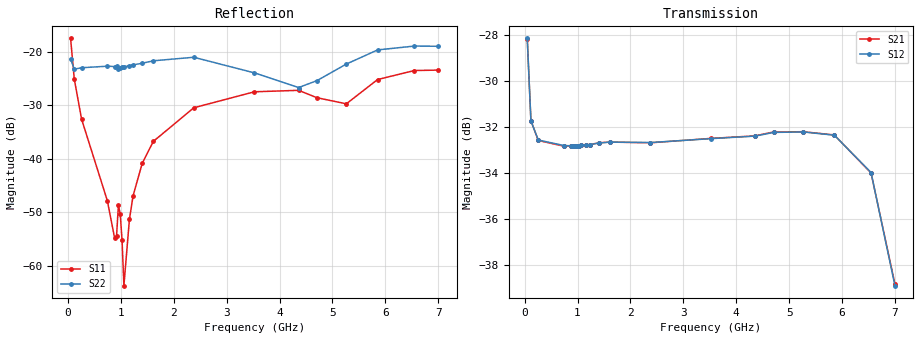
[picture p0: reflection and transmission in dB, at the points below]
! Integrated Device Technology
! Corporate Headquarters
! 6024 Silver Creek Valley Road
! San Jose, CA 95138  USA
! Phone:  1-408-284-8200
! Toll Free:  1-800-223-1366
! Webpage:  http://www.idt.com/
! Timing and RF Division
! 515 Groton Road, Suite 102
! Westford, MA 01886-6024
! Device:  F2258
! Description: Voltage Variable RF Attenuator
! Frequency:  50.0 -  6000.00 MHz
! Package:  3x3 mm Thin QFN Plastic Package: 16 pin
! Ports:  2 RF, 2 DC
!  Pin  1  = NC
!  Pin  2  = NC
!  Pin  3  = RF2  = Port 2
!  Pin  4  = GND
!  Pin  5  = Vdd
!  Pin  6  = NC
!  Pin  7  = VCTRL
!  Pin  8  = NC
!  Pin  9  = GND
!  Pin 10  = RF1  = Port 1
!  Pin 11  = NC
!  Pin 12  = NC
!  Pin 13  = NC
!  Pin 14  = NC
!  Pin 15  = NC
!  Pin 16  = NC
! Vcntrl:  1.770 Volts
! Vdd:  +3.300 Volts
! Current:  1.158 mA
! Data:  The device was measured on a the F2258 evaluation board which has
!  individual transmission lines to the RF pins.  Data was collected
!  using a calibrated network analyzer.  The evaluation board was
!  de-embedded using a TRL calibration technique.
!  The reference plane is the edge of the package pin.
! Misc:  SN 10
!  Action Tracker AT0285
! Date Measured:  2014-12-10
! Date:  2016-01-13  MJV
! Note:
!  Integrated Device Technology supplies this data as a sample of measured
!  data at the package pin for this product.  Your particular data for this
!  product may vary.
!  Data was taken at 25 degrees C.
!  Integrated Device Technology reserves the right to change this data at anytime.
!Freq_(GHz)  S11M_(dB)  S11P_(deg)  S21M_(dB)  S21P_(deg)  S12M_(dB)  S12P_(deg)  S22M_(dB)  S22P_(deg)
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# GHz S dB R 50
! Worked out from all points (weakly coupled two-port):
!   201 points, 50 MHz to 7 GHz, reference 50 ohm
!   highest |S21| = -28.17 dB at 50 MHz (marker M1); lowest = -38.8 dB at 7 GHz (marker M2)
!   lowest |S11| = -63.7 dB at 1.058 GHz (marker M3), VSWR 1.00, Z = 49.9 + j0.0344 ohm
!   |S11| at or under -10 dB: start of sweep to end of sweep
!   |S22| runs from -26.7 to -18.8 dB; largest |S21 - S12| = 0.00014
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0.05  -17.53 -110.5  -28.17 -58.2  -28.16 -58.2  -21.34 -80.4
0.1195  -25.10 -106.1  -31.73 -30.7  -31.74 -30.7  -23.30 -30.3
0.2585  -32.64 -110.1  -32.59 -16.3  -32.57 -16.3  -23.02 -13.1
0.745  -47.86 -136.0  -32.84 -9.8  -32.81 -9.9  -22.73 -7.3
0.884  -54.92 167.8  -32.83 -9.8  -32.82 -9.8  -22.79 -8.3
0.91875  -54.53 145.4  -32.83 -9.9  -32.81 -9.9  -22.77 -8.6
0.9535  -48.74 -156.8  -32.83 -9.9  -32.84 -9.9  -23.19 -7.1
0.98825  -50.29 -169.0  -32.83 -9.9  -32.82 -9.9  -23.11 -7.9
1.023  -55.26 179.6  -32.82 -9.9  -32.82 -9.9  -22.97 -8.2
1.05775  -63.74 148.0  -32.80 -10.0  -32.80 -10.0  -22.84 -8.1
1.162  -51.37 55.6  -32.78 -10.3  -32.78 -10.3  -22.64 -8.7
1.2315  -46.92 38.4  -32.77 -10.5  -32.77 -10.5  -22.48 -9.0
1.40525  -40.85 30.2  -32.69 -11.6  -32.70 -11.5  -22.18 -9.4
1.61375  -36.78 30.4  -32.66 -13.0  -32.66 -13.0  -21.72 -11.2
2.37825  -30.50 46.9  -32.69 -17.9  -32.68 -17.9  -21.06 -13.7
3.525  -27.51 91.0  -32.50 -26.2  -32.51 -26.2  -23.98 -18.6
4.359  -27.24 104.5  -32.39 -33.2  -32.40 -33.2  -26.72 -33.0
4.7065  -28.62 95.2  -32.22 -36.4  -32.24 -36.3  -25.43 -40.5
5.2625  -29.76 53.4  -32.21 -42.6  -32.22 -42.6  -22.33 -45.1
5.85325  -25.22 29.2  -32.35 -52.1  -32.36 -52.1  -19.69 -45.3
6.54825  -23.54 44.6  -34.00 -69.0  -33.98 -69.0  -18.97 -69.7
7  -23.46 84.1  -38.82 -67.1  -38.89 -66.9  -19.01 -123.3
